One B-rep face of a CAD part: STEP entity #26989.
In plain terms, the planar face has unit normal (0, 1, 0).
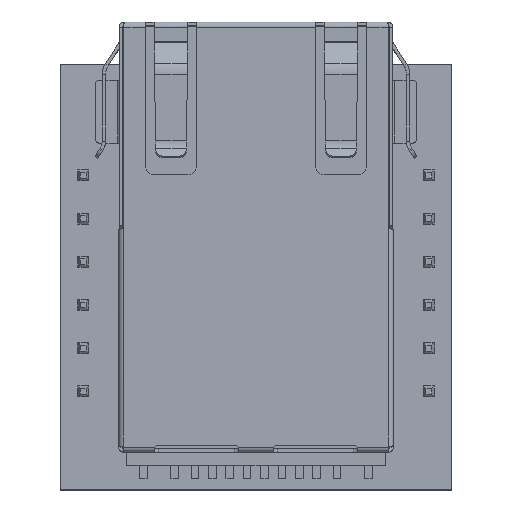
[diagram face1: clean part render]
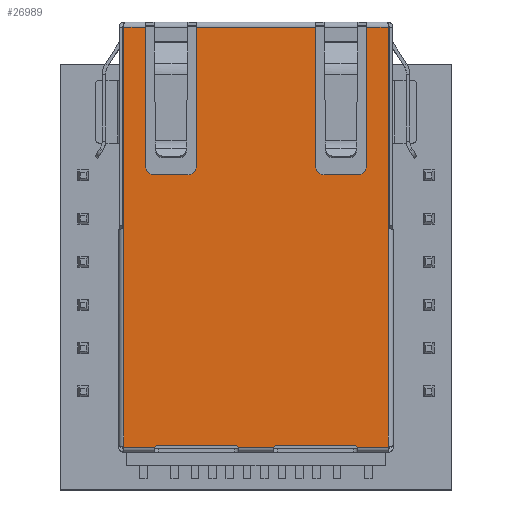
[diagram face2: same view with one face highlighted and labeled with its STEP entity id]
Its self-contained STEP definition (entity closure, numbers rounded to 3 decimals):
#26117 = VERTEX_POINT('',#26118);
#26118 = CARTESIAN_POINT('',(4.,6.75,-8.986));
#26126 = VERTEX_POINT('',#26127);
#26127 = CARTESIAN_POINT('',(3.5,6.75,-8.486));
#26133 = EDGE_CURVE('',#26126,#26117,#26134,.T.);
#26134 = CIRCLE('',#26135,0.5);
#26135 = AXIS2_PLACEMENT_3D('',#26136,#26137,#26138);
#26136 = CARTESIAN_POINT('',(4.,6.75,-8.486));
#26137 = DIRECTION('',(0.,-1.,0.));
#26138 = DIRECTION('',(0.,0.,1.));
#26167 = EDGE_CURVE('',#26168,#26126,#26170,.T.);
#26168 = VERTEX_POINT('',#26169);
#26169 = CARTESIAN_POINT('',(3.5,6.75,-0.3));
#26170 = LINE('',#26171,#26172);
#26171 = CARTESIAN_POINT('',(3.5,6.75,-0.2));
#26172 = VECTOR('',#26173,1.);
#26173 = DIRECTION('',(0.,0.,-1.));
#26224 = VERTEX_POINT('',#26225);
#26225 = CARTESIAN_POINT('',(-3.5,6.75,-0.3));
#26232 = EDGE_CURVE('',#26233,#26224,#26235,.T.);
#26233 = VERTEX_POINT('',#26234);
#26234 = CARTESIAN_POINT('',(-3.5,6.75,-8.486));
#26235 = LINE('',#26236,#26237);
#26236 = CARTESIAN_POINT('',(-3.5,6.75,-0.2));
#26237 = VECTOR('',#26238,1.);
#26238 = DIRECTION('',(0.,0.,1.));
#26259 = VERTEX_POINT('',#26260);
#26260 = CARTESIAN_POINT('',(-4.,6.75,-8.986));
#26266 = EDGE_CURVE('',#26259,#26233,#26267,.T.);
#26267 = CIRCLE('',#26268,0.5);
#26268 = AXIS2_PLACEMENT_3D('',#26269,#26270,#26271);
#26269 = CARTESIAN_POINT('',(-4.,6.75,-8.486));
#26270 = DIRECTION('',(0.,-1.,0.));
#26271 = DIRECTION('',(0.,0.,1.));
#26283 = EDGE_CURVE('',#26284,#26259,#26286,.T.);
#26284 = VERTEX_POINT('',#26285);
#26285 = CARTESIAN_POINT('',(-6.,6.75,-8.986));
#26286 = LINE('',#26287,#26288);
#26287 = CARTESIAN_POINT('',(-4.,6.75,-8.986));
#26288 = VECTOR('',#26289,1.);
#26289 = DIRECTION('',(1.,0.,0.));
#26306 = VERTEX_POINT('',#26307);
#26307 = CARTESIAN_POINT('',(-6.5,6.75,-8.486));
#26313 = EDGE_CURVE('',#26306,#26284,#26314,.T.);
#26314 = CIRCLE('',#26315,0.5);
#26315 = AXIS2_PLACEMENT_3D('',#26316,#26317,#26318);
#26316 = CARTESIAN_POINT('',(-6.,6.75,-8.486));
#26317 = DIRECTION('',(0.,-1.,0.));
#26318 = DIRECTION('',(0.,0.,-1.));
#26349 = EDGE_CURVE('',#26350,#26306,#26352,.T.);
#26350 = VERTEX_POINT('',#26351);
#26351 = CARTESIAN_POINT('',(-6.5,6.75,-0.3));
#26352 = LINE('',#26353,#26354);
#26353 = CARTESIAN_POINT('',(-6.5,6.75,-0.2));
#26354 = VECTOR('',#26355,1.);
#26355 = DIRECTION('',(0.,0.,-1.));
#26410 = VERTEX_POINT('',#26411);
#26411 = CARTESIAN_POINT('',(-7.779,6.75,-12.132));
#26419 = VERTEX_POINT('',#26420);
#26420 = CARTESIAN_POINT('',(-7.779,6.75,-0.3));
#26426 = EDGE_CURVE('',#26419,#26410,#26427,.T.);
#26427 = LINE('',#26428,#26429);
#26428 = CARTESIAN_POINT('',(-7.779,6.75,-25.));
#26429 = VECTOR('',#26430,1.);
#26430 = DIRECTION('',(0.,0.,-1.));
#26526 = VERTEX_POINT('',#26527);
#26527 = CARTESIAN_POINT('',(-5.75,6.75,-24.907));
#26533 = EDGE_CURVE('',#26526,#26534,#26536,.T.);
#26534 = VERTEX_POINT('',#26535);
#26535 = CARTESIAN_POINT('',(-5.944,6.75,-25.));
#26536 = CIRCLE('',#26537,0.25);
#26537 = AXIS2_PLACEMENT_3D('',#26538,#26539,#26540);
#26538 = CARTESIAN_POINT('',(-5.75,6.75,-25.157));
#26539 = DIRECTION('',(0.,-1.,0.));
#26540 = DIRECTION('',(0.,0.,1.));
#26557 = EDGE_CURVE('',#26558,#26526,#26560,.T.);
#26558 = VERTEX_POINT('',#26559);
#26559 = CARTESIAN_POINT('',(-1.25,6.75,-24.907));
#26560 = LINE('',#26561,#26562);
#26561 = CARTESIAN_POINT('',(-1.25,6.75,-24.907));
#26562 = VECTOR('',#26563,1.);
#26563 = DIRECTION('',(-1.,0.,0.));
#26580 = EDGE_CURVE('',#26581,#26558,#26583,.T.);
#26581 = VERTEX_POINT('',#26582);
#26582 = CARTESIAN_POINT('',(-1.056,6.75,-25.));
#26583 = CIRCLE('',#26584,0.25);
#26584 = AXIS2_PLACEMENT_3D('',#26585,#26586,#26587);
#26585 = CARTESIAN_POINT('',(-1.25,6.75,-25.157));
#26586 = DIRECTION('',(0.,-1.,0.));
#26587 = DIRECTION('',(0.,0.,1.));
#26640 = VERTEX_POINT('',#26641);
#26641 = CARTESIAN_POINT('',(1.25,6.75,-24.907));
#26647 = EDGE_CURVE('',#26640,#26648,#26650,.T.);
#26648 = VERTEX_POINT('',#26649);
#26649 = CARTESIAN_POINT('',(1.056,6.75,-25.));
#26650 = CIRCLE('',#26651,0.25);
#26651 = AXIS2_PLACEMENT_3D('',#26652,#26653,#26654);
#26652 = CARTESIAN_POINT('',(1.25,6.75,-25.157));
#26653 = DIRECTION('',(0.,-1.,0.));
#26654 = DIRECTION('',(0.,0.,1.));
#26671 = EDGE_CURVE('',#26672,#26640,#26674,.T.);
#26672 = VERTEX_POINT('',#26673);
#26673 = CARTESIAN_POINT('',(5.75,6.75,-24.907));
#26674 = LINE('',#26675,#26676);
#26675 = CARTESIAN_POINT('',(1.25,6.75,-24.907));
#26676 = VECTOR('',#26677,1.);
#26677 = DIRECTION('',(-1.,0.,0.));
#26694 = EDGE_CURVE('',#26695,#26672,#26697,.T.);
#26695 = VERTEX_POINT('',#26696);
#26696 = CARTESIAN_POINT('',(5.944,6.75,-25.));
#26697 = CIRCLE('',#26698,0.25);
#26698 = AXIS2_PLACEMENT_3D('',#26699,#26700,#26701);
#26699 = CARTESIAN_POINT('',(5.75,6.75,-25.157));
#26700 = DIRECTION('',(0.,-1.,0.));
#26701 = DIRECTION('',(0.,0.,1.));
#26805 = VERTEX_POINT('',#26806);
#26806 = CARTESIAN_POINT('',(7.779,6.75,-12.132));
#26812 = EDGE_CURVE('',#26805,#26813,#26815,.T.);
#26813 = VERTEX_POINT('',#26814);
#26814 = CARTESIAN_POINT('',(7.779,6.75,-0.3));
#26815 = LINE('',#26816,#26817);
#26816 = CARTESIAN_POINT('',(7.779,6.75,-0.2));
#26817 = VECTOR('',#26818,1.);
#26818 = DIRECTION('',(0.,0.,1.));
#26888 = VERTEX_POINT('',#26889);
#26889 = CARTESIAN_POINT('',(6.5,6.75,-0.3));
#26896 = EDGE_CURVE('',#26897,#26888,#26899,.T.);
#26897 = VERTEX_POINT('',#26898);
#26898 = CARTESIAN_POINT('',(6.5,6.75,-8.486));
#26899 = LINE('',#26900,#26901);
#26900 = CARTESIAN_POINT('',(6.5,6.75,-0.2));
#26901 = VECTOR('',#26902,1.);
#26902 = DIRECTION('',(0.,0.,1.));
#26923 = VERTEX_POINT('',#26924);
#26924 = CARTESIAN_POINT('',(6.,6.75,-8.986));
#26930 = EDGE_CURVE('',#26923,#26897,#26931,.T.);
#26931 = CIRCLE('',#26932,0.5);
#26932 = AXIS2_PLACEMENT_3D('',#26933,#26934,#26935);
#26933 = CARTESIAN_POINT('',(6.,6.75,-8.486));
#26934 = DIRECTION('',(0.,-1.,0.));
#26935 = DIRECTION('',(0.,0.,1.));
#26945 = EDGE_CURVE('',#26117,#26923,#26946,.T.);
#26946 = LINE('',#26947,#26948);
#26947 = CARTESIAN_POINT('',(4.,6.75,-8.986));
#26948 = VECTOR('',#26949,1.);
#26949 = DIRECTION('',(1.,0.,0.));
#26989 = ADVANCED_FACE('',(#26990),#27062,.T.);
#26990 = FACE_BOUND('',#26991,.T.);
#26991 = EDGE_LOOP('',(#26992,#26993,#26994,#26995,#26996,#26997,#27003,
    #27004,#27005,#27006,#27007,#27008,#27014,#27015,#27023,#27029,
    #27030,#27031,#27032,#27038,#27039,#27040,#27041,#27049,#27055,
    #27056));
#26992 = ORIENTED_EDGE('',*,*,#26349,.T.);
#26993 = ORIENTED_EDGE('',*,*,#26313,.T.);
#26994 = ORIENTED_EDGE('',*,*,#26283,.T.);
#26995 = ORIENTED_EDGE('',*,*,#26266,.T.);
#26996 = ORIENTED_EDGE('',*,*,#26232,.T.);
#26997 = ORIENTED_EDGE('',*,*,#26998,.T.);
#26998 = EDGE_CURVE('',#26224,#26168,#26999,.T.);
#26999 = LINE('',#27000,#27001);
#27000 = CARTESIAN_POINT('',(7.75,6.75,-0.3));
#27001 = VECTOR('',#27002,1.);
#27002 = DIRECTION('',(1.,0.,0.));
#27003 = ORIENTED_EDGE('',*,*,#26167,.T.);
#27004 = ORIENTED_EDGE('',*,*,#26133,.T.);
#27005 = ORIENTED_EDGE('',*,*,#26945,.T.);
#27006 = ORIENTED_EDGE('',*,*,#26930,.T.);
#27007 = ORIENTED_EDGE('',*,*,#26896,.T.);
#27008 = ORIENTED_EDGE('',*,*,#27009,.T.);
#27009 = EDGE_CURVE('',#26888,#26813,#27010,.T.);
#27010 = LINE('',#27011,#27012);
#27011 = CARTESIAN_POINT('',(7.75,6.75,-0.3));
#27012 = VECTOR('',#27013,1.);
#27013 = DIRECTION('',(1.,0.,0.));
#27014 = ORIENTED_EDGE('',*,*,#26812,.F.);
#27015 = ORIENTED_EDGE('',*,*,#27016,.T.);
#27016 = EDGE_CURVE('',#26805,#27017,#27019,.T.);
#27017 = VERTEX_POINT('',#27018);
#27018 = CARTESIAN_POINT('',(7.779,6.75,-25.));
#27019 = LINE('',#27020,#27021);
#27020 = CARTESIAN_POINT('',(7.779,6.75,-0.2));
#27021 = VECTOR('',#27022,1.);
#27022 = DIRECTION('',(0.,0.,-1.));
#27023 = ORIENTED_EDGE('',*,*,#27024,.T.);
#27024 = EDGE_CURVE('',#27017,#26695,#27025,.T.);
#27025 = LINE('',#27026,#27027);
#27026 = CARTESIAN_POINT('',(7.75,6.75,-25.));
#27027 = VECTOR('',#27028,1.);
#27028 = DIRECTION('',(-1.,0.,0.));
#27029 = ORIENTED_EDGE('',*,*,#26694,.T.);
#27030 = ORIENTED_EDGE('',*,*,#26671,.T.);
#27031 = ORIENTED_EDGE('',*,*,#26647,.T.);
#27032 = ORIENTED_EDGE('',*,*,#27033,.T.);
#27033 = EDGE_CURVE('',#26648,#26581,#27034,.T.);
#27034 = LINE('',#27035,#27036);
#27035 = CARTESIAN_POINT('',(7.75,6.75,-25.));
#27036 = VECTOR('',#27037,1.);
#27037 = DIRECTION('',(-1.,0.,0.));
#27038 = ORIENTED_EDGE('',*,*,#26580,.T.);
#27039 = ORIENTED_EDGE('',*,*,#26557,.T.);
#27040 = ORIENTED_EDGE('',*,*,#26533,.T.);
#27041 = ORIENTED_EDGE('',*,*,#27042,.T.);
#27042 = EDGE_CURVE('',#26534,#27043,#27045,.T.);
#27043 = VERTEX_POINT('',#27044);
#27044 = CARTESIAN_POINT('',(-7.779,6.75,-25.));
#27045 = LINE('',#27046,#27047);
#27046 = CARTESIAN_POINT('',(7.75,6.75,-25.));
#27047 = VECTOR('',#27048,1.);
#27048 = DIRECTION('',(-1.,0.,0.));
#27049 = ORIENTED_EDGE('',*,*,#27050,.T.);
#27050 = EDGE_CURVE('',#27043,#26410,#27051,.T.);
#27051 = LINE('',#27052,#27053);
#27052 = CARTESIAN_POINT('',(-7.779,6.75,-0.2));
#27053 = VECTOR('',#27054,1.);
#27054 = DIRECTION('',(0.,0.,1.));
#27055 = ORIENTED_EDGE('',*,*,#26426,.F.);
#27056 = ORIENTED_EDGE('',*,*,#27057,.T.);
#27057 = EDGE_CURVE('',#26419,#26350,#27058,.T.);
#27058 = LINE('',#27059,#27060);
#27059 = CARTESIAN_POINT('',(7.75,6.75,-0.3));
#27060 = VECTOR('',#27061,1.);
#27061 = DIRECTION('',(1.,0.,0.));
#27062 = PLANE('',#27063);
#27063 = AXIS2_PLACEMENT_3D('',#27064,#27065,#27066);
#27064 = CARTESIAN_POINT('',(7.75,6.75,-0.2));
#27065 = DIRECTION('',(0.,1.,0.));
#27066 = DIRECTION('',(0.,0.,1.));
